VERSION 5.8 ;
BUSBITCHARS "[]" ;
DIVIDERCHAR "/" ;

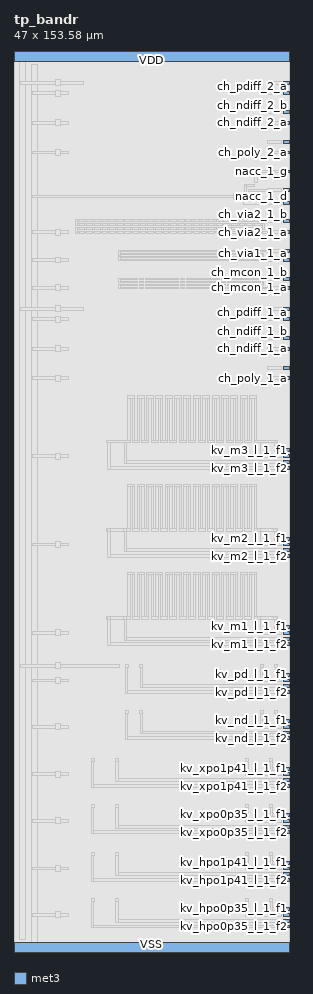
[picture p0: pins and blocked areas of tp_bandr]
MACRO tp_bandr
  CLASS BLOCK ;
  FOREIGN tp_bandr 0 0 ;
  ORIGIN 0 0 ;
  SIZE 47.000 BY 153.580 ;
  SYMMETRY X Y ;
  PIN VDD
    DIRECTION INOUT ;
    USE POWER ;
    PORT
      LAYER met3 ;
        RECT 0.000 151.980 47.000 153.580 ;
    END
  END VDD
  PIN VSS
    DIRECTION INOUT ;
    USE GROUND ;
    PORT
      LAYER met3 ;
        RECT 0.000 0.000 47.000 1.600 ;
    END
  END VSS
  PIN ch_mcon_1_a
    DIRECTION INOUT ;
    USE SIGNAL ;
    PORT
      LAYER met3 ;
        RECT 46.000 113.085 47.000 113.585 ;
    END
  END ch_mcon_1_a
  PIN ch_mcon_1_b
    DIRECTION INOUT ;
    USE SIGNAL ;
    PORT
      LAYER met3 ;
        RECT 46.000 114.585 47.000 115.085 ;
    END
  END ch_mcon_1_b
  PIN ch_ndiff_1_a
    DIRECTION INOUT ;
    USE SIGNAL ;
    PORT
      LAYER met3 ;
        RECT 46.000 102.685 47.000 103.185 ;
    END
  END ch_ndiff_1_a
  PIN ch_ndiff_1_b
    DIRECTION INOUT ;
    USE SIGNAL ;
    PORT
      LAYER met3 ;
        RECT 46.000 104.485 47.000 104.985 ;
    END
  END ch_ndiff_1_b
  PIN ch_ndiff_2_a
    DIRECTION INOUT ;
    USE SIGNAL ;
    PORT
      LAYER met3 ;
        RECT 46.000 141.235 47.000 141.735 ;
    END
  END ch_ndiff_2_a
  PIN ch_ndiff_2_b
    DIRECTION INOUT ;
    USE SIGNAL ;
    PORT
      LAYER met3 ;
        RECT 46.000 143.035 47.000 143.535 ;
    END
  END ch_ndiff_2_b
  PIN ch_pdiff_1_a
    DIRECTION INOUT ;
    USE SIGNAL ;
    PORT
      LAYER met3 ;
        RECT 46.000 107.735 47.000 108.235 ;
    END
  END ch_pdiff_1_a
  PIN ch_pdiff_1_b
    DIRECTION INOUT ;
    USE SIGNAL ;
    PORT
      LAYER met3 ;
        RECT 46.000 109.535 47.000 110.035 ;
    END
  END ch_pdiff_1_b
  PIN ch_pdiff_2_a
    DIRECTION INOUT ;
    USE SIGNAL ;
    PORT
      LAYER met3 ;
        RECT 46.000 146.285 47.000 146.785 ;
    END
  END ch_pdiff_2_a
  PIN ch_pdiff_2_b
    DIRECTION INOUT ;
    USE SIGNAL ;
    PORT
      LAYER met3 ;
        RECT 46.000 148.085 47.000 148.585 ;
    END
  END ch_pdiff_2_b
  PIN ch_poly_1_a
    DIRECTION INOUT ;
    USE SIGNAL ;
    PORT
      LAYER met3 ;
        RECT 46.000 97.635 47.000 98.135 ;
    END
  END ch_poly_1_a
  PIN ch_poly_1_b
    DIRECTION INOUT ;
    USE SIGNAL ;
    PORT
      LAYER met3 ;
        RECT 46.000 99.435 47.000 99.935 ;
    END
  END ch_poly_1_b
  PIN ch_poly_2_a
    DIRECTION INOUT ;
    USE SIGNAL ;
    PORT
      LAYER met3 ;
        RECT 46.000 136.185 47.000 136.685 ;
    END
  END ch_poly_2_a
  PIN ch_poly_2_b
    DIRECTION INOUT ;
    USE SIGNAL ;
    PORT
      LAYER met3 ;
        RECT 46.000 137.985 47.000 138.485 ;
    END
  END ch_poly_2_b
  PIN ch_via1_1_a
    DIRECTION INOUT ;
    USE SIGNAL ;
    PORT
      LAYER met3 ;
        RECT 46.000 117.835 47.000 118.335 ;
    END
  END ch_via1_1_a
  PIN ch_via1_1_b
    DIRECTION INOUT ;
    USE SIGNAL ;
    PORT
      LAYER met3 ;
        RECT 46.000 119.335 47.000 119.835 ;
    END
  END ch_via1_1_b
  PIN ch_via2_1_a
    DIRECTION INOUT ;
    USE SIGNAL ;
    PORT
      LAYER met3 ;
        RECT 46.000 122.585 47.000 123.085 ;
    END
  END ch_via2_1_a
  PIN ch_via2_1_b
    DIRECTION INOUT ;
    USE SIGNAL ;
    PORT
      LAYER met3 ;
        RECT 46.000 124.535 47.000 125.035 ;
    END
  END ch_via2_1_b
  PIN kv_hpo0p35_l_1_f1
    DIRECTION INOUT ;
    USE SIGNAL ;
    PORT
      LAYER met3 ;
        RECT 46.000 7.100 47.000 7.600 ;
    END
  END kv_hpo0p35_l_1_f1
  PIN kv_hpo0p35_l_1_f2
    DIRECTION INOUT ;
    USE SIGNAL ;
    PORT
      LAYER met3 ;
        RECT 46.000 4.100 47.000 4.600 ;
    END
  END kv_hpo0p35_l_1_f2
  PIN kv_hpo0p35_l_1_s1
    DIRECTION INOUT ;
    USE SIGNAL ;
    PORT
      LAYER met3 ;
        RECT 46.000 6.100 47.000 6.600 ;
    END
  END kv_hpo0p35_l_1_s1
  PIN kv_hpo0p35_l_1_s2
    DIRECTION INOUT ;
    USE SIGNAL ;
    PORT
      LAYER met3 ;
        RECT 46.000 5.100 47.000 5.600 ;
    END
  END kv_hpo0p35_l_1_s2
  PIN kv_hpo1p41_l_1_f1
    DIRECTION INOUT ;
    USE SIGNAL ;
    PORT
      LAYER met3 ;
        RECT 46.000 15.000 47.000 15.500 ;
    END
  END kv_hpo1p41_l_1_f1
  PIN kv_hpo1p41_l_1_f2
    DIRECTION INOUT ;
    USE SIGNAL ;
    PORT
      LAYER met3 ;
        RECT 46.000 12.000 47.000 12.500 ;
    END
  END kv_hpo1p41_l_1_f2
  PIN kv_hpo1p41_l_1_s1
    DIRECTION INOUT ;
    USE SIGNAL ;
    PORT
      LAYER met3 ;
        RECT 46.000 14.000 47.000 14.500 ;
    END
  END kv_hpo1p41_l_1_s1
  PIN kv_hpo1p41_l_1_s2
    DIRECTION INOUT ;
    USE SIGNAL ;
    PORT
      LAYER met3 ;
        RECT 46.000 13.000 47.000 13.500 ;
    END
  END kv_hpo1p41_l_1_s2
  PIN kv_m1_l_1_f1
    DIRECTION INOUT ;
    USE SIGNAL ;
    PORT
      LAYER met3 ;
        RECT 46.000 55.235 47.000 55.735 ;
    END
  END kv_m1_l_1_f1
  PIN kv_m1_l_1_f2
    DIRECTION INOUT ;
    USE SIGNAL ;
    PORT
      LAYER met3 ;
        RECT 46.000 52.235 47.000 52.735 ;
    END
  END kv_m1_l_1_f2
  PIN kv_m1_l_1_s1
    DIRECTION INOUT ;
    USE SIGNAL ;
    PORT
      LAYER met3 ;
        RECT 46.000 54.235 47.000 54.735 ;
    END
  END kv_m1_l_1_s1
  PIN kv_m1_l_1_s2
    DIRECTION INOUT ;
    USE SIGNAL ;
    PORT
      LAYER met3 ;
        RECT 46.000 53.235 47.000 53.735 ;
    END
  END kv_m1_l_1_s2
  PIN kv_m2_l_1_f1
    DIRECTION INOUT ;
    USE SIGNAL ;
    PORT
      LAYER met3 ;
        RECT 46.000 70.285 47.000 70.785 ;
    END
  END kv_m2_l_1_f1
  PIN kv_m2_l_1_f2
    DIRECTION INOUT ;
    USE SIGNAL ;
    PORT
      LAYER met3 ;
        RECT 46.000 67.285 47.000 67.785 ;
    END
  END kv_m2_l_1_f2
  PIN kv_m2_l_1_s1
    DIRECTION INOUT ;
    USE SIGNAL ;
    PORT
      LAYER met3 ;
        RECT 46.000 69.285 47.000 69.785 ;
    END
  END kv_m2_l_1_s1
  PIN kv_m2_l_1_s2
    DIRECTION INOUT ;
    USE SIGNAL ;
    PORT
      LAYER met3 ;
        RECT 46.000 68.285 47.000 68.785 ;
    END
  END kv_m2_l_1_s2
  PIN kv_m3_l_1_f1
    DIRECTION INOUT ;
    USE SIGNAL ;
    PORT
      LAYER met3 ;
        RECT 46.000 85.335 47.000 85.835 ;
    END
  END kv_m3_l_1_f1
  PIN kv_m3_l_1_f2
    DIRECTION INOUT ;
    USE SIGNAL ;
    PORT
      LAYER met3 ;
        RECT 46.000 82.335 47.000 82.835 ;
    END
  END kv_m3_l_1_f2
  PIN kv_m3_l_1_s1
    DIRECTION INOUT ;
    USE SIGNAL ;
    PORT
      LAYER met3 ;
        RECT 46.000 84.335 47.000 84.835 ;
    END
  END kv_m3_l_1_s1
  PIN kv_m3_l_1_s2
    DIRECTION INOUT ;
    USE SIGNAL ;
    PORT
      LAYER met3 ;
        RECT 46.000 83.335 47.000 83.835 ;
    END
  END kv_m3_l_1_s2
  PIN kv_nd_l_1_f1
    DIRECTION INOUT ;
    USE SIGNAL ;
    PORT
      LAYER met3 ;
        RECT 46.000 39.210 47.000 39.710 ;
    END
  END kv_nd_l_1_f1
  PIN kv_nd_l_1_f2
    DIRECTION INOUT ;
    USE SIGNAL ;
    PORT
      LAYER met3 ;
        RECT 46.000 36.210 47.000 36.710 ;
    END
  END kv_nd_l_1_f2
  PIN kv_nd_l_1_s1
    DIRECTION INOUT ;
    USE SIGNAL ;
    PORT
      LAYER met3 ;
        RECT 46.000 38.210 47.000 38.710 ;
    END
  END kv_nd_l_1_s1
  PIN kv_nd_l_1_s2
    DIRECTION INOUT ;
    USE SIGNAL ;
    PORT
      LAYER met3 ;
        RECT 46.000 37.210 47.000 37.710 ;
    END
  END kv_nd_l_1_s2
  PIN kv_pd_l_1_f1
    DIRECTION INOUT ;
    USE SIGNAL ;
    PORT
      LAYER met3 ;
        RECT 46.000 47.085 47.000 47.585 ;
    END
  END kv_pd_l_1_f1
  PIN kv_pd_l_1_f2
    DIRECTION INOUT ;
    USE SIGNAL ;
    PORT
      LAYER met3 ;
        RECT 46.000 44.085 47.000 44.585 ;
    END
  END kv_pd_l_1_f2
  PIN kv_pd_l_1_s1
    DIRECTION INOUT ;
    USE SIGNAL ;
    PORT
      LAYER met3 ;
        RECT 46.000 46.085 47.000 46.585 ;
    END
  END kv_pd_l_1_s1
  PIN kv_pd_l_1_s2
    DIRECTION INOUT ;
    USE SIGNAL ;
    PORT
      LAYER met3 ;
        RECT 46.000 45.085 47.000 45.585 ;
    END
  END kv_pd_l_1_s2
  PIN kv_xpo0p35_l_1_f1
    DIRECTION INOUT ;
    USE SIGNAL ;
    PORT
      LAYER met3 ;
        RECT 46.000 23.155 47.000 23.655 ;
    END
  END kv_xpo0p35_l_1_f1
  PIN kv_xpo0p35_l_1_f2
    DIRECTION INOUT ;
    USE SIGNAL ;
    PORT
      LAYER met3 ;
        RECT 46.000 20.155 47.000 20.655 ;
    END
  END kv_xpo0p35_l_1_f2
  PIN kv_xpo0p35_l_1_s1
    DIRECTION INOUT ;
    USE SIGNAL ;
    PORT
      LAYER met3 ;
        RECT 46.000 22.155 47.000 22.655 ;
    END
  END kv_xpo0p35_l_1_s1
  PIN kv_xpo0p35_l_1_s2
    DIRECTION INOUT ;
    USE SIGNAL ;
    PORT
      LAYER met3 ;
        RECT 46.000 21.155 47.000 21.655 ;
    END
  END kv_xpo0p35_l_1_s2
  PIN kv_xpo1p41_l_1_f1
    DIRECTION INOUT ;
    USE SIGNAL ;
    PORT
      LAYER met3 ;
        RECT 46.000 31.055 47.000 31.555 ;
    END
  END kv_xpo1p41_l_1_f1
  PIN kv_xpo1p41_l_1_f2
    DIRECTION INOUT ;
    USE SIGNAL ;
    PORT
      LAYER met3 ;
        RECT 46.000 28.055 47.000 28.555 ;
    END
  END kv_xpo1p41_l_1_f2
  PIN kv_xpo1p41_l_1_s1
    DIRECTION INOUT ;
    USE SIGNAL ;
    PORT
      LAYER met3 ;
        RECT 46.000 30.055 47.000 30.555 ;
    END
  END kv_xpo1p41_l_1_s1
  PIN kv_xpo1p41_l_1_s2
    DIRECTION INOUT ;
    USE SIGNAL ;
    PORT
      LAYER met3 ;
        RECT 46.000 29.055 47.000 29.555 ;
    END
  END kv_xpo1p41_l_1_s2
  PIN nacc_1_d
    DIRECTION INOUT ;
    USE SIGNAL ;
    PORT
      LAYER met3 ;
        RECT 46.000 127.535 47.000 128.035 ;
    END
  END nacc_1_d
  PIN nacc_1_g
    DIRECTION INOUT ;
    USE SIGNAL ;
    PORT
      LAYER met3 ;
        RECT 46.000 132.935 47.000 133.435 ;
    END
  END nacc_1_g
  PIN nacc_1_s
    DIRECTION INOUT ;
    USE SIGNAL ;
    PORT
      LAYER met3 ;
        RECT 46.000 129.725 47.000 130.225 ;
    END
  END nacc_1_s
  OBS
    LAYER li1 ;
      RECT 0.000 0.000 47.000 153.580 ;
    LAYER met1 ;
      RECT 19.400 57.185 19.800 64.385 ;
      RECT 15.800 56.785 19.800 57.185 ;
      RECT 21.000 57.185 21.400 64.385 ;
      RECT 20.200 56.785 21.400 57.185 ;
      RECT 22.600 57.185 23.000 64.385 ;
      RECT 21.800 56.785 23.000 57.185 ;
      RECT 24.200 57.185 24.600 64.385 ;
      RECT 23.400 56.785 24.600 57.185 ;
      RECT 25.800 57.185 26.200 64.385 ;
      RECT 25.000 56.785 26.200 57.185 ;
      RECT 27.400 57.185 27.800 64.385 ;
      RECT 26.600 56.785 27.800 57.185 ;
      RECT 29.000 57.185 29.400 64.385 ;
      RECT 28.200 56.785 29.400 57.185 ;
      RECT 30.600 57.185 31.000 64.385 ;
      RECT 29.800 56.785 31.000 57.185 ;
      RECT 32.200 57.185 32.600 64.385 ;
      RECT 31.400 56.785 32.600 57.185 ;
      RECT 33.800 57.185 34.200 64.385 ;
      RECT 33.000 56.785 34.200 57.185 ;
      RECT 35.400 57.185 35.800 64.385 ;
      RECT 34.600 56.785 35.800 57.185 ;
      RECT 37.000 57.185 37.400 64.385 ;
      RECT 36.200 56.785 37.400 57.185 ;
      RECT 38.600 57.185 39.000 64.385 ;
      RECT 37.800 56.785 39.000 57.185 ;
      RECT 40.200 57.185 40.600 64.385 ;
      RECT 39.400 56.785 40.600 57.185 ;
      RECT 19.400 64.385 20.600 64.785 ;
      RECT 20.200 57.185 20.600 64.385 ;
      RECT 21.000 64.385 22.200 64.785 ;
      RECT 21.800 57.185 22.200 64.385 ;
      RECT 22.600 64.385 23.800 64.785 ;
      RECT 23.400 57.185 23.800 64.385 ;
      RECT 24.200 64.385 25.400 64.785 ;
      RECT 25.000 57.185 25.400 64.385 ;
      RECT 25.800 64.385 27.000 64.785 ;
      RECT 26.600 57.185 27.000 64.385 ;
      RECT 27.400 64.385 28.600 64.785 ;
      RECT 28.200 57.185 28.600 64.385 ;
      RECT 29.000 64.385 30.200 64.785 ;
      RECT 29.800 57.185 30.200 64.385 ;
      RECT 30.600 64.385 31.800 64.785 ;
      RECT 31.400 57.185 31.800 64.385 ;
      RECT 32.200 64.385 33.400 64.785 ;
      RECT 33.000 57.185 33.400 64.385 ;
      RECT 33.800 64.385 35.000 64.785 ;
      RECT 34.600 57.185 35.000 64.385 ;
      RECT 35.400 64.385 36.600 64.785 ;
      RECT 36.200 57.185 36.600 64.385 ;
      RECT 37.000 64.385 38.200 64.785 ;
      RECT 37.800 57.185 38.200 64.385 ;
      RECT 38.600 64.385 39.800 64.785 ;
      RECT 39.400 57.185 39.800 64.385 ;
      RECT 41.000 56.785 45.000 57.185 ;
      RECT 40.200 64.385 41.400 64.785 ;
      RECT 41.000 57.185 41.400 64.385 ;
      RECT 26.355 113.220 27.145 113.450 ;
      RECT 26.355 113.720 27.145 113.950 ;
      RECT 26.355 114.220 27.145 114.450 ;
      RECT 26.355 114.720 27.145 114.950 ;
      RECT 26.840 117.955 27.660 118.215 ;
      RECT 26.840 118.455 27.660 118.715 ;
      RECT 26.840 118.955 27.660 119.215 ;
      RECT 26.840 119.455 27.660 119.715 ;
      RECT 35.355 113.220 36.145 113.450 ;
      RECT 35.355 113.720 36.145 113.950 ;
      RECT 35.355 114.220 36.145 114.450 ;
      RECT 35.355 114.720 36.145 114.950 ;
      RECT 35.840 117.955 36.660 118.215 ;
      RECT 35.840 118.455 36.660 118.715 ;
      RECT 35.840 118.955 36.660 119.215 ;
      RECT 35.840 119.455 36.660 119.715 ;
      RECT 36.355 113.220 37.145 113.450 ;
      RECT 36.355 113.720 37.145 113.950 ;
      RECT 37.355 113.720 38.145 113.950 ;
      RECT 38.355 113.720 39.145 113.950 ;
      RECT 39.355 113.720 40.145 113.950 ;
      RECT 40.355 113.720 41.145 113.950 ;
      RECT 41.355 113.720 42.145 113.950 ;
      RECT 37.355 113.220 38.145 113.450 ;
      RECT 36.355 114.220 37.145 114.450 ;
      RECT 37.355 114.220 38.145 114.450 ;
      RECT 38.355 114.220 39.145 114.450 ;
      RECT 39.355 114.220 40.145 114.450 ;
      RECT 40.355 114.220 41.145 114.450 ;
      RECT 41.355 114.220 42.145 114.450 ;
      RECT 42.385 113.690 42.615 114.480 ;
      RECT 38.355 113.220 39.145 113.450 ;
      RECT 36.355 114.720 37.145 114.950 ;
      RECT 37.355 114.720 38.145 114.950 ;
      RECT 38.355 114.720 39.145 114.950 ;
      RECT 39.355 114.720 40.145 114.950 ;
      RECT 40.355 114.720 41.145 114.950 ;
      RECT 41.355 114.720 42.145 114.950 ;
      RECT 42.355 114.720 43.340 114.950 ;
      RECT 43.340 114.675 43.660 114.995 ;
      RECT 39.355 113.220 40.145 113.450 ;
      RECT 36.840 117.955 37.660 118.215 ;
      RECT 37.840 117.955 38.660 118.215 ;
      RECT 38.840 117.955 39.660 118.215 ;
      RECT 39.840 117.955 40.660 118.215 ;
      RECT 40.840 117.955 41.660 118.215 ;
      RECT 41.840 117.955 42.660 118.215 ;
      RECT 40.355 113.220 41.145 113.450 ;
      RECT 36.840 118.455 37.660 118.715 ;
      RECT 37.840 118.455 38.660 118.715 ;
      RECT 38.840 118.455 39.660 118.715 ;
      RECT 39.840 118.455 40.660 118.715 ;
      RECT 40.840 118.455 41.660 118.715 ;
      RECT 41.840 118.455 42.660 118.715 ;
      RECT 41.355 113.220 42.145 113.450 ;
      RECT 36.840 118.955 37.660 119.215 ;
      RECT 37.840 118.955 38.660 119.215 ;
      RECT 38.840 118.955 39.660 119.215 ;
      RECT 39.840 118.955 40.660 119.215 ;
      RECT 40.840 118.955 41.660 119.215 ;
      RECT 41.840 118.955 42.660 119.215 ;
      RECT 42.355 113.220 43.340 113.450 ;
      RECT 43.340 113.175 43.660 113.495 ;
      RECT 36.840 119.455 37.660 119.715 ;
      RECT 37.840 119.455 38.660 119.715 ;
      RECT 38.840 119.455 39.660 119.715 ;
      RECT 39.840 119.455 40.660 119.715 ;
      RECT 40.840 119.455 41.660 119.715 ;
      RECT 41.840 119.455 42.660 119.715 ;
      RECT 40.000 128.545 41.820 129.295 ;
      RECT 39.980 129.830 43.390 130.120 ;
      RECT 43.710 129.830 43.800 130.120 ;
      RECT 43.390 129.815 43.710 130.135 ;
      RECT 39.335 130.630 41.055 130.920 ;
      RECT 41.150 131.345 41.470 131.665 ;
      RECT 43.340 136.275 43.660 136.595 ;
      RECT 43.340 138.075 43.660 138.395 ;
      RECT 43.340 141.325 43.660 141.645 ;
      RECT 43.340 143.125 43.660 143.445 ;
      RECT 43.340 146.375 43.660 146.695 ;
      RECT 43.340 148.175 43.660 148.495 ;
      RECT 34.840 117.955 35.660 118.215 ;
      RECT 28.355 114.220 29.145 114.450 ;
      RECT 29.355 114.220 30.145 114.450 ;
      RECT 30.355 114.220 31.145 114.450 ;
      RECT 31.355 114.220 32.145 114.450 ;
      RECT 32.355 114.220 33.145 114.450 ;
      RECT 33.355 114.220 34.145 114.450 ;
      RECT 34.355 114.220 35.145 114.450 ;
      RECT 27.840 118.455 28.660 118.715 ;
      RECT 28.840 118.455 29.660 118.715 ;
      RECT 29.840 118.455 30.660 118.715 ;
      RECT 30.840 118.455 31.660 118.715 ;
      RECT 31.840 118.455 32.660 118.715 ;
      RECT 32.840 118.455 33.660 118.715 ;
      RECT 33.840 118.455 34.660 118.715 ;
      RECT 34.840 118.455 35.660 118.715 ;
      RECT 27.355 113.720 28.145 113.950 ;
      RECT 28.355 113.720 29.145 113.950 ;
      RECT 29.355 113.720 30.145 113.950 ;
      RECT 30.355 113.720 31.145 113.950 ;
      RECT 31.355 113.720 32.145 113.950 ;
      RECT 32.355 113.720 33.145 113.950 ;
      RECT 33.355 113.720 34.145 113.950 ;
      RECT 27.840 118.955 28.660 119.215 ;
      RECT 28.840 118.955 29.660 119.215 ;
      RECT 29.840 118.955 30.660 119.215 ;
      RECT 30.840 118.955 31.660 119.215 ;
      RECT 31.840 118.955 32.660 119.215 ;
      RECT 32.840 118.955 33.660 119.215 ;
      RECT 33.840 118.955 34.660 119.215 ;
      RECT 34.840 118.955 35.660 119.215 ;
      RECT 34.355 113.720 35.145 113.950 ;
      RECT 27.355 114.720 28.145 114.950 ;
      RECT 28.355 114.720 29.145 114.950 ;
      RECT 29.355 114.720 30.145 114.950 ;
      RECT 30.355 114.720 31.145 114.950 ;
      RECT 31.355 114.720 32.145 114.950 ;
      RECT 32.355 114.720 33.145 114.950 ;
      RECT 27.355 113.220 28.145 113.450 ;
      RECT 27.840 119.455 28.660 119.715 ;
      RECT 28.840 119.455 29.660 119.715 ;
      RECT 29.840 119.455 30.660 119.715 ;
      RECT 30.840 119.455 31.660 119.715 ;
      RECT 31.840 119.455 32.660 119.715 ;
      RECT 32.840 119.455 33.660 119.715 ;
      RECT 33.840 119.455 34.660 119.715 ;
      RECT 34.840 119.455 35.660 119.715 ;
      RECT 33.355 114.720 34.145 114.950 ;
      RECT 34.355 114.720 35.145 114.950 ;
      RECT 29.355 113.220 30.145 113.450 ;
      RECT 30.355 113.220 31.145 113.450 ;
      RECT 31.355 113.220 32.145 113.450 ;
      RECT 32.355 113.220 33.145 113.450 ;
      RECT 33.355 113.220 34.145 113.450 ;
      RECT 34.355 113.220 35.145 113.450 ;
      RECT 28.355 113.220 29.145 113.450 ;
      RECT 27.355 114.220 28.145 114.450 ;
      RECT 27.840 117.955 28.660 118.215 ;
      RECT 28.840 117.955 29.660 118.215 ;
      RECT 29.840 117.955 30.660 118.215 ;
      RECT 30.840 117.955 31.660 118.215 ;
      RECT 31.840 117.955 32.660 118.215 ;
      RECT 32.840 117.955 33.660 118.215 ;
      RECT 33.840 117.955 34.660 118.215 ;
      RECT 43.340 97.725 43.660 98.045 ;
      RECT 43.340 107.825 43.660 108.145 ;
      RECT 43.340 102.775 43.660 103.095 ;
      RECT 43.340 104.575 43.660 104.895 ;
      RECT 43.340 99.525 43.660 99.845 ;
      RECT 43.340 109.625 43.660 109.945 ;
      RECT 25.840 118.455 26.660 118.715 ;
      RECT 20.355 114.720 21.145 114.950 ;
      RECT 21.355 114.720 22.145 114.950 ;
      RECT 22.355 114.720 23.145 114.950 ;
      RECT 23.355 114.720 24.145 114.950 ;
      RECT 24.355 114.720 25.145 114.950 ;
      RECT 25.355 114.720 26.145 114.950 ;
      RECT 8.840 102.775 9.160 103.095 ;
      RECT 8.840 113.175 9.160 113.495 ;
      RECT 11.440 109.625 11.760 109.945 ;
      RECT 18.355 113.720 19.145 113.950 ;
      RECT 19.355 113.720 20.145 113.950 ;
      RECT 17.885 113.190 18.115 113.980 ;
      RECT 18.355 114.220 19.145 114.450 ;
      RECT 19.355 114.220 20.145 114.450 ;
      RECT 20.355 114.220 21.145 114.450 ;
      RECT 21.355 114.220 22.145 114.450 ;
      RECT 17.840 118.955 18.660 119.215 ;
      RECT 18.840 118.955 19.660 119.215 ;
      RECT 19.840 118.955 20.660 119.215 ;
      RECT 20.840 118.955 21.660 119.215 ;
      RECT 21.840 118.955 22.660 119.215 ;
      RECT 22.840 118.955 23.660 119.215 ;
      RECT 23.840 118.955 24.660 119.215 ;
      RECT 24.840 118.955 25.660 119.215 ;
      RECT 25.840 118.955 26.660 119.215 ;
      RECT 22.355 114.220 23.145 114.450 ;
      RECT 23.355 114.220 24.145 114.450 ;
      RECT 24.355 114.220 25.145 114.450 ;
      RECT 25.355 114.220 26.145 114.450 ;
      RECT 20.355 113.720 21.145 113.950 ;
      RECT 21.355 113.720 22.145 113.950 ;
      RECT 17.885 114.190 18.115 114.980 ;
      RECT 22.355 113.720 23.145 113.950 ;
      RECT 17.840 117.955 18.660 118.215 ;
      RECT 18.840 117.955 19.660 118.215 ;
      RECT 19.840 117.955 20.660 118.215 ;
      RECT 20.840 117.955 21.660 118.215 ;
      RECT 21.840 117.955 22.660 118.215 ;
      RECT 22.840 117.955 23.660 118.215 ;
      RECT 23.840 117.955 24.660 118.215 ;
      RECT 24.840 117.955 25.660 118.215 ;
      RECT 17.840 119.455 18.660 119.715 ;
      RECT 18.840 119.455 19.660 119.715 ;
      RECT 19.840 119.455 20.660 119.715 ;
      RECT 20.840 119.455 21.660 119.715 ;
      RECT 21.840 119.455 22.660 119.715 ;
      RECT 22.840 119.455 23.660 119.715 ;
      RECT 23.840 119.455 24.660 119.715 ;
      RECT 24.840 119.455 25.660 119.715 ;
      RECT 25.840 119.455 26.660 119.715 ;
      RECT 25.840 117.955 26.660 118.215 ;
      RECT 23.355 113.720 24.145 113.950 ;
      RECT 24.355 113.720 25.145 113.950 ;
      RECT 25.355 113.720 26.145 113.950 ;
      RECT 8.840 84.425 9.160 84.745 ;
      RECT 18.355 113.220 19.145 113.450 ;
      RECT 19.355 113.220 20.145 113.450 ;
      RECT 20.355 113.220 21.145 113.450 ;
      RECT 21.355 113.220 22.145 113.450 ;
      RECT 22.355 113.220 23.145 113.450 ;
      RECT 23.355 113.220 24.145 113.450 ;
      RECT 24.355 113.220 25.145 113.450 ;
      RECT 25.355 113.220 26.145 113.450 ;
      RECT 8.840 97.725 9.160 98.045 ;
      RECT 8.840 107.825 9.160 108.145 ;
      RECT 18.355 114.720 19.145 114.950 ;
      RECT 8.840 122.675 9.160 122.995 ;
      RECT 19.355 114.720 20.145 114.950 ;
      RECT 8.840 117.925 9.160 118.245 ;
      RECT 17.840 118.455 18.660 118.715 ;
      RECT 18.840 118.455 19.660 118.715 ;
      RECT 8.840 136.275 9.160 136.595 ;
      RECT 19.840 118.455 20.660 118.715 ;
      RECT 20.840 118.455 21.660 118.715 ;
      RECT 8.840 141.325 9.160 141.645 ;
      RECT 21.840 118.455 22.660 118.715 ;
      RECT 22.840 118.455 23.660 118.715 ;
      RECT 8.840 146.375 9.160 146.695 ;
      RECT 23.840 118.455 24.660 118.715 ;
      RECT 11.440 148.175 11.760 148.495 ;
      RECT 24.840 118.455 25.660 118.715 ;
      RECT 8.840 6.190 9.160 6.510 ;
      RECT 8.840 69.375 9.160 69.695 ;
      RECT 13.280 8.690 13.600 9.010 ;
      RECT 17.440 8.690 17.760 9.010 ;
      RECT 8.840 14.090 9.160 14.410 ;
      RECT 13.280 16.590 13.600 16.910 ;
      RECT 17.440 16.590 17.760 16.910 ;
      RECT 8.840 22.245 9.160 22.565 ;
      RECT 13.280 24.745 13.600 25.065 ;
      RECT 17.440 24.745 17.760 25.065 ;
      RECT 8.840 30.145 9.160 30.465 ;
      RECT 13.280 32.645 13.600 32.965 ;
      RECT 17.440 32.645 17.760 32.965 ;
      RECT 8.840 38.300 9.160 38.620 ;
      RECT 19.090 40.800 19.410 41.120 ;
      RECT 21.590 40.800 21.910 41.120 ;
      RECT 8.840 46.175 9.160 46.495 ;
      RECT 17.540 48.675 17.860 48.995 ;
      RECT 19.090 48.675 19.410 48.995 ;
      RECT 21.590 48.675 21.910 48.995 ;
      RECT 8.840 54.325 9.160 54.645 ;
      RECT 42.090 40.800 42.410 41.120 ;
      RECT 44.590 40.800 44.910 41.120 ;
      RECT 43.760 16.590 44.080 16.910 ;
      RECT 43.760 8.690 44.080 9.010 ;
      RECT 39.600 8.690 39.920 9.010 ;
      RECT 39.600 32.645 39.920 32.965 ;
      RECT 42.090 48.675 42.410 48.995 ;
      RECT 44.590 48.675 44.910 48.995 ;
      RECT 43.760 32.645 44.080 32.965 ;
      RECT 39.600 16.590 39.920 16.910 ;
      RECT 39.600 24.745 39.920 25.065 ;
      RECT 43.760 24.745 44.080 25.065 ;
    LAYER met2 ;
      RECT 19.400 72.235 19.800 79.435 ;
      RECT 15.800 71.835 19.800 72.235 ;
      RECT 21.000 72.235 21.400 79.435 ;
      RECT 20.200 71.835 21.400 72.235 ;
      RECT 22.600 72.235 23.000 79.435 ;
      RECT 21.800 71.835 23.000 72.235 ;
      RECT 24.200 72.235 24.600 79.435 ;
      RECT 23.400 71.835 24.600 72.235 ;
      RECT 25.800 72.235 26.200 79.435 ;
      RECT 25.000 71.835 26.200 72.235 ;
      RECT 27.400 72.235 27.800 79.435 ;
      RECT 26.600 71.835 27.800 72.235 ;
      RECT 29.000 72.235 29.400 79.435 ;
      RECT 28.200 71.835 29.400 72.235 ;
      RECT 30.600 72.235 31.000 79.435 ;
      RECT 29.800 71.835 31.000 72.235 ;
      RECT 32.200 72.235 32.600 79.435 ;
      RECT 31.400 71.835 32.600 72.235 ;
      RECT 33.800 72.235 34.200 79.435 ;
      RECT 33.000 71.835 34.200 72.235 ;
      RECT 35.400 72.235 35.800 79.435 ;
      RECT 34.600 71.835 35.800 72.235 ;
      RECT 37.000 72.235 37.400 79.435 ;
      RECT 36.200 71.835 37.400 72.235 ;
      RECT 38.600 72.235 39.000 79.435 ;
      RECT 37.800 71.835 39.000 72.235 ;
      RECT 40.200 72.235 40.600 79.435 ;
      RECT 39.400 71.835 40.600 72.235 ;
      RECT 19.400 79.435 20.600 79.835 ;
      RECT 20.200 72.235 20.600 79.435 ;
      RECT 21.000 79.435 22.200 79.835 ;
      RECT 21.800 72.235 22.200 79.435 ;
      RECT 22.600 79.435 23.800 79.835 ;
      RECT 23.400 72.235 23.800 79.435 ;
      RECT 24.200 79.435 25.400 79.835 ;
      RECT 25.000 72.235 25.400 79.435 ;
      RECT 25.800 79.435 27.000 79.835 ;
      RECT 26.600 72.235 27.000 79.435 ;
      RECT 27.400 79.435 28.600 79.835 ;
      RECT 28.200 72.235 28.600 79.435 ;
      RECT 29.000 79.435 30.200 79.835 ;
      RECT 29.800 72.235 30.200 79.435 ;
      RECT 30.600 79.435 31.800 79.835 ;
      RECT 31.400 72.235 31.800 79.435 ;
      RECT 32.200 79.435 33.400 79.835 ;
      RECT 33.000 72.235 33.400 79.435 ;
      RECT 33.800 79.435 35.000 79.835 ;
      RECT 34.600 72.235 35.000 79.435 ;
      RECT 35.400 79.435 36.600 79.835 ;
      RECT 36.200 72.235 36.600 79.435 ;
      RECT 37.000 79.435 38.200 79.835 ;
      RECT 37.800 72.235 38.200 79.435 ;
      RECT 38.600 79.435 39.800 79.835 ;
      RECT 39.400 72.235 39.800 79.435 ;
      RECT 41.000 71.835 45.000 72.235 ;
      RECT 40.200 79.435 41.400 79.835 ;
      RECT 41.000 72.235 41.400 79.435 ;
      RECT 22.340 117.955 23.160 118.215 ;
      RECT 22.340 118.455 23.160 118.715 ;
      RECT 22.340 118.955 23.160 119.215 ;
      RECT 22.340 119.455 23.160 119.715 ;
      RECT 22.165 122.695 23.185 122.975 ;
      RECT 22.165 123.345 23.185 123.625 ;
      RECT 22.165 123.995 23.185 124.275 ;
      RECT 22.165 124.645 23.185 124.925 ;
      RECT 3.000 0.200 4.000 151.380 ;
      RECT 1.000 2.200 2.000 153.380 ;
      RECT 33.340 117.955 34.160 118.215 ;
      RECT 33.340 118.455 34.160 118.715 ;
      RECT 33.340 118.955 34.160 119.215 ;
      RECT 33.340 119.455 34.160 119.715 ;
      RECT 33.865 122.695 34.885 122.975 ;
      RECT 33.865 123.345 34.885 123.625 ;
      RECT 33.865 123.995 34.885 124.275 ;
      RECT 33.865 124.645 34.885 124.925 ;
      RECT 41.340 117.955 42.160 118.215 ;
      RECT 42.340 117.955 43.315 118.215 ;
      RECT 43.315 117.900 43.685 118.270 ;
      RECT 34.340 117.955 35.160 118.215 ;
      RECT 34.340 118.455 35.160 118.715 ;
      RECT 35.340 118.455 36.160 118.715 ;
      RECT 36.340 118.455 37.160 118.715 ;
      RECT 37.340 118.455 38.160 118.715 ;
      RECT 38.340 118.455 39.160 118.715 ;
      RECT 39.340 118.455 40.160 118.715 ;
      RECT 40.340 118.455 41.160 118.715 ;
      RECT 41.340 118.455 42.160 118.715 ;
      RECT 35.340 117.955 36.160 118.215 ;
      RECT 34.340 118.955 35.160 119.215 ;
      RECT 35.340 118.955 36.160 119.215 ;
      RECT 36.340 118.955 37.160 119.215 ;
      RECT 37.340 118.955 38.160 119.215 ;
      RECT 38.340 118.955 39.160 119.215 ;
      RECT 39.340 118.955 40.160 119.215 ;
      RECT 40.340 118.955 41.160 119.215 ;
      RECT 41.340 118.955 42.160 119.215 ;
      RECT 42.370 118.425 42.630 119.245 ;
      RECT 36.340 117.955 37.160 118.215 ;
      RECT 34.340 119.455 35.160 119.715 ;
      RECT 35.340 119.455 36.160 119.715 ;
      RECT 36.340 119.455 37.160 119.715 ;
      RECT 37.340 119.455 38.160 119.715 ;
      RECT 38.340 119.455 39.160 119.715 ;
      RECT 39.340 119.455 40.160 119.715 ;
      RECT 40.340 119.455 41.160 119.715 ;
      RECT 41.340 119.455 42.160 119.715 ;
      RECT 42.340 119.455 43.315 119.715 ;
      RECT 43.315 119.400 43.685 119.770 ;
      RECT 37.340 117.955 38.160 118.215 ;
      RECT 35.165 122.695 36.185 122.975 ;
      RECT 36.465 122.695 37.485 122.975 ;
      RECT 37.765 122.695 38.785 122.975 ;
      RECT 39.065 122.695 40.085 122.975 ;
      RECT 40.365 122.695 41.385 122.975 ;
      RECT 41.665 122.695 42.685 122.975 ;
      RECT 38.340 117.955 39.160 118.215 ;
      RECT 35.165 123.345 36.185 123.625 ;
      RECT 36.465 123.345 37.485 123.625 ;
      RECT 37.765 123.345 38.785 123.625 ;
      RECT 39.065 123.345 40.085 123.625 ;
      RECT 40.365 123.345 41.385 123.625 ;
      RECT 41.665 123.345 42.685 123.625 ;
      RECT 39.340 117.955 40.160 118.215 ;
      RECT 35.165 123.995 36.185 124.275 ;
      RECT 36.465 123.995 37.485 124.275 ;
      RECT 37.765 123.995 38.785 124.275 ;
      RECT 39.065 123.995 40.085 124.275 ;
      RECT 40.365 123.995 41.385 124.275 ;
      RECT 41.665 123.995 42.685 124.275 ;
      RECT 40.340 117.955 41.160 118.215 ;
      RECT 35.165 124.645 36.185 124.925 ;
      RECT 36.465 124.645 37.485 124.925 ;
      RECT 37.765 124.645 38.785 124.925 ;
      RECT 39.065 124.645 40.085 124.925 ;
      RECT 40.365 124.645 41.385 124.925 ;
      RECT 41.665 124.645 42.685 124.925 ;
      RECT 40.615 128.735 40.985 129.105 ;
      RECT 43.365 129.790 43.735 130.160 ;
      RECT 39.365 130.785 39.625 130.935 ;
      RECT 39.335 127.970 39.655 130.785 ;
      RECT 39.310 127.600 39.680 127.970 ;
      RECT 41.125 131.305 41.495 133.370 ;
      RECT 43.315 136.250 43.685 136.620 ;
      RECT 43.315 138.050 43.685 138.420 ;
      RECT 43.315 141.300 43.685 141.670 ;
      RECT 43.315 143.100 43.685 143.470 ;
      RECT 43.315 146.350 43.685 146.720 ;
      RECT 43.315 148.150 43.685 148.520 ;
      RECT 23.340 118.955 24.160 119.215 ;
      RECT 23.465 122.695 24.485 122.975 ;
      RECT 24.765 122.695 25.785 122.975 ;
      RECT 26.065 122.695 27.085 122.975 ;
      RECT 27.365 122.695 28.385 122.975 ;
      RECT 28.665 122.695 29.685 122.975 ;
      RECT 29.965 122.695 30.985 122.975 ;
      RECT 31.265 122.695 32.285 122.975 ;
      RECT 32.565 122.695 33.585 122.975 ;
      RECT 24.340 118.955 25.160 119.215 ;
      RECT 25.340 118.955 26.160 119.215 ;
      RECT 26.340 118.955 27.160 119.215 ;
      RECT 27.340 118.955 28.160 119.215 ;
      RECT 28.340 118.955 29.160 119.215 ;
      RECT 29.340 118.955 30.160 119.215 ;
      RECT 30.340 118.955 31.160 119.215 ;
      RECT 23.465 123.345 24.485 123.625 ;
      RECT 24.765 123.345 25.785 123.625 ;
      RECT 26.065 123.345 27.085 123.625 ;
      RECT 27.365 123.345 28.385 123.625 ;
      RECT 28.665 123.345 29.685 123.625 ;
      RECT 29.965 123.345 30.985 123.625 ;
      RECT 31.265 123.345 32.285 123.625 ;
      RECT 32.565 123.345 33.585 123.625 ;
      RECT 31.340 118.955 32.160 119.215 ;
      RECT 32.340 118.955 33.160 119.215 ;
      RECT 23.340 118.455 24.160 118.715 ;
      RECT 24.340 118.455 25.160 118.715 ;
      RECT 25.340 118.455 26.160 118.715 ;
      RECT 26.340 118.455 27.160 118.715 ;
      RECT 27.340 118.455 28.160 118.715 ;
      RECT 23.465 123.995 24.485 124.275 ;
      RECT 24.765 123.995 25.785 124.275 ;
      RECT 26.065 123.995 27.085 124.275 ;
      RECT 27.365 123.995 28.385 124.275 ;
      RECT 28.665 123.995 29.685 124.275 ;
      RECT 29.965 123.995 30.985 124.275 ;
      RECT 31.265 123.995 32.285 124.275 ;
      RECT 32.565 123.995 33.585 124.275 ;
      RECT 28.340 118.455 29.160 118.715 ;
      RECT 29.340 118.455 30.160 118.715 ;
      RECT 30.340 118.455 31.160 118.715 ;
      RECT 31.340 118.455 32.160 118.715 ;
      RECT 32.340 118.455 33.160 118.715 ;
      RECT 23.340 119.455 24.160 119.715 ;
      RECT 24.340 119.455 25.160 119.715 ;
      RECT 23.465 124.645 24.485 124.925 ;
      RECT 24.765 124.645 25.785 124.925 ;
      RECT 26.065 124.645 27.085 124.925 ;
      RECT 27.365 124.645 28.385 124.925 ;
      RECT 28.665 124.645 29.685 124.925 ;
      RECT 29.965 124.645 30.985 124.925 ;
      RECT 31.265 124.645 32.285 124.925 ;
      RECT 32.565 124.645 33.585 124.925 ;
      RECT 25.340 119.455 26.160 119.715 ;
      RECT 26.340 119.455 27.160 119.715 ;
      RECT 27.340 119.455 28.160 119.715 ;
      RECT 28.340 119.455 29.160 119.715 ;
      RECT 29.340 119.455 30.160 119.715 ;
      RECT 30.340 119.455 31.160 119.715 ;
      RECT 31.340 119.455 32.160 119.715 ;
      RECT 32.340 119.455 33.160 119.715 ;
      RECT 25.340 117.955 26.160 118.215 ;
      RECT 26.340 117.955 27.160 118.215 ;
      RECT 27.340 117.955 28.160 118.215 ;
      RECT 28.340 117.955 29.160 118.215 ;
      RECT 29.340 117.955 30.160 118.215 ;
      RECT 30.340 117.955 31.160 118.215 ;
      RECT 31.340 117.955 32.160 118.215 ;
      RECT 32.340 117.955 33.160 118.215 ;
      RECT 24.340 117.955 25.160 118.215 ;
      RECT 23.340 117.955 24.160 118.215 ;
      RECT 43.315 99.500 43.685 99.870 ;
      RECT 43.315 114.650 43.685 115.020 ;
      RECT 43.315 102.750 43.685 103.120 ;
      RECT 43.315 109.600 43.685 109.970 ;
      RECT 43.315 113.150 43.685 113.520 ;
      RECT 43.315 107.800 43.685 108.170 ;
      RECT 43.315 97.700 43.685 98.070 ;
      RECT 43.315 104.550 43.685 104.920 ;
      RECT 10.465 123.995 11.485 124.275 ;
      RECT 11.765 123.995 12.785 124.275 ;
      RECT 13.065 123.995 14.085 124.275 ;
      RECT 14.365 123.995 15.385 124.275 ;
      RECT 15.665 123.995 16.685 124.275 ;
      RECT 16.965 123.995 17.985 124.275 ;
      RECT 18.265 123.995 19.285 124.275 ;
      RECT 19.565 123.995 20.585 124.275 ;
      RECT 20.865 123.995 21.885 124.275 ;
      RECT 19.565 122.695 20.585 122.975 ;
      RECT 20.865 122.695 21.885 122.975 ;
      RECT 19.340 119.455 20.160 119.715 ;
      RECT 20.340 119.455 21.160 119.715 ;
      RECT 21.340 119.455 22.160 119.715 ;
      RECT 19.340 117.955 20.160 118.215 ;
      RECT 20.340 117.955 21.160 118.215 ;
      RECT 21.340 117.955 22.160 118.215 ;
      RECT 8.815 117.900 9.185 118.270 ;
      RECT 8.815 102.750 9.185 103.120 ;
      RECT 18.340 118.455 19.160 118.715 ;
      RECT 19.340 118.455 20.160 118.715 ;
      RECT 20.340 118.455 21.160 118.715 ;
      RECT 21.340 118.455 22.160 118.715 ;
      RECT 11.415 109.600 11.785 109.970 ;
      RECT 8.815 84.400 9.185 84.770 ;
      RECT 10.465 124.645 11.485 124.925 ;
      RECT 11.765 124.645 12.785 124.925 ;
      RECT 13.065 124.645 14.085 124.925 ;
      RECT 14.365 124.645 15.385 124.925 ;
      RECT 15.665 124.645 16.685 124.925 ;
      RECT 16.965 124.645 17.985 124.925 ;
      RECT 18.265 124.645 19.285 124.925 ;
      RECT 19.565 124.645 20.585 124.925 ;
      RECT 20.865 124.645 21.885 124.925 ;
      RECT 8.815 113.150 9.185 113.520 ;
      RECT 8.815 97.700 9.185 98.070 ;
      RECT 8.815 122.650 9.185 123.020 ;
      RECT 10.465 123.345 11.485 123.625 ;
      RECT 11.765 123.345 12.785 123.625 ;
      RECT 13.065 123.345 14.085 123.625 ;
      RECT 14.365 123.345 15.385 123.625 ;
      RECT 15.665 123.345 16.685 123.625 ;
      RECT 16.965 123.345 17.985 123.625 ;
      RECT 18.265 123.345 19.285 123.625 ;
      RECT 19.565 123.345 20.585 123.625 ;
      RECT 20.865 123.345 21.885 123.625 ;
      RECT 8.815 107.800 9.185 108.170 ;
      RECT 17.870 117.925 18.130 118.745 ;
      RECT 18.340 118.955 19.160 119.215 ;
      RECT 19.340 118.955 20.160 119.215 ;
      RECT 20.340 118.955 21.160 119.215 ;
      RECT 21.340 118.955 22.160 119.215 ;
      RECT 18.340 117.955 19.160 118.215 ;
      RECT 17.870 118.925 18.130 119.745 ;
      RECT 8.815 136.250 9.185 136.620 ;
      RECT 18.340 119.455 19.160 119.715 ;
      RECT 10.465 122.695 11.485 122.975 ;
      RECT 8.815 141.300 9.185 141.670 ;
      RECT 11.765 122.695 12.785 122.975 ;
      RECT 13.065 122.695 14.085 122.975 ;
      RECT 8.815 146.350 9.185 146.720 ;
      RECT 14.365 122.695 15.385 122.975 ;
      RECT 11.415 148.150 11.785 148.520 ;
      RECT 15.665 122.695 16.685 122.975 ;
      RECT 16.965 122.695 17.985 122.975 ;
      RECT 18.265 122.695 19.285 122.975 ;
      RECT 13.255 16.565 13.625 16.935 ;
      RECT 17.415 16.565 17.785 16.935 ;
      RECT 8.815 22.220 9.185 22.590 ;
      RECT 13.255 24.720 13.625 25.090 ;
      RECT 17.415 24.720 17.785 25.090 ;
      RECT 8.815 30.120 9.185 30.490 ;
      RECT 13.255 32.620 13.625 32.990 ;
      RECT 17.415 32.620 17.785 32.990 ;
      RECT 8.815 38.275 9.185 38.645 ;
      RECT 19.065 40.775 19.435 41.145 ;
      RECT 21.565 40.775 21.935 41.145 ;
      RECT 8.815 46.150 9.185 46.520 ;
      RECT 17.515 48.650 17.885 49.020 ;
      RECT 19.065 48.650 19.435 49.020 ;
      RECT 21.565 48.650 21.935 49.020 ;
      RECT 8.815 54.300 9.185 54.670 ;
      RECT 16.015 56.800 16.385 57.170 ;
      RECT 18.815 56.800 19.185 57.170 ;
      RECT 8.815 69.350 9.185 69.720 ;
      RECT 8.815 6.165 9.185 6.535 ;
      RECT 13.255 8.665 13.625 9.035 ;
      RECT 17.415 8.665 17.785 9.035 ;
      RECT 8.815 14.065 9.185 14.435 ;
      RECT 39.575 24.720 39.945 25.090 ;
      RECT 41.615 56.800 41.985 57.170 ;
      RECT 44.415 56.800 44.785 57.170 ;
      RECT 43.735 24.720 44.105 25.090 ;
      RECT 42.065 40.775 42.435 41.145 ;
      RECT 44.565 40.775 44.935 41.145 ;
      RECT 43.735 16.565 44.105 16.935 ;
      RECT 43.735 8.665 44.105 9.035 ;
      RECT 39.575 8.665 39.945 9.035 ;
      RECT 39.575 32.620 39.945 32.990 ;
      RECT 42.065 48.650 42.435 49.020 ;
      RECT 44.565 48.650 44.935 49.020 ;
      RECT 43.735 32.620 44.105 32.990 ;
      RECT 39.575 16.565 39.945 16.935 ;
    LAYER met3 ;
      RECT 13.190 8.600 13.690 9.100 ;
      RECT 13.640 4.100 45.700 4.600 ;
      RECT 13.240 4.100 13.640 8.600 ;
      RECT 17.350 8.600 17.850 9.100 ;
      RECT 17.800 5.100 45.700 5.600 ;
      RECT 17.400 5.100 17.800 8.600 ;
      RECT 13.190 16.500 13.690 17.000 ;
      RECT 13.640 12.000 45.700 12.500 ;
      RECT 13.240 12.000 13.640 16.500 ;
      RECT 17.350 16.500 17.850 17.000 ;
      RECT 17.800 13.000 45.700 13.500 ;
      RECT 17.400 13.000 17.800 16.500 ;
      RECT 13.190 24.655 13.690 25.155 ;
      RECT 13.640 20.155 45.700 20.655 ;
      RECT 13.240 20.155 13.640 24.655 ;
      RECT 17.350 24.655 17.850 25.155 ;
      RECT 17.800 21.155 45.700 21.655 ;
      RECT 17.400 21.155 17.800 24.655 ;
      RECT 13.190 32.555 13.690 33.055 ;
      RECT 13.640 28.055 45.700 28.555 ;
      RECT 13.240 28.055 13.640 32.555 ;
      RECT 17.350 32.555 17.850 33.055 ;
      RECT 17.800 29.055 45.700 29.555 ;
      RECT 17.400 29.055 17.800 32.555 ;
      RECT 19.000 40.710 19.500 41.210 ;
      RECT 19.450 36.210 45.700 36.710 ;
      RECT 19.050 36.210 19.450 40.710 ;
      RECT 21.500 40.710 22.000 41.210 ;
      RECT 21.950 37.210 45.700 37.710 ;
      RECT 21.550 37.210 21.950 40.710 ;
      RECT 19.000 48.585 19.500 49.085 ;
      RECT 19.450 44.085 45.700 44.585 ;
      RECT 19.050 44.085 19.450 48.585 ;
      RECT 21.500 48.585 22.000 49.085 ;
      RECT 21.950 45.085 45.700 45.585 ;
      RECT 21.550 45.085 21.950 48.585 ;
      RECT 15.950 56.735 16.450 57.235 ;
      RECT 16.400 52.235 45.700 52.735 ;
      RECT 16.000 52.235 16.400 56.735 ;
      RECT 18.750 56.735 19.250 57.235 ;
      RECT 19.200 53.235 45.700 53.735 ;
      RECT 18.800 53.235 19.200 56.735 ;
      RECT 15.950 71.785 16.450 72.285 ;
      RECT 16.400 67.285 45.700 67.785 ;
      RECT 16.000 67.285 16.400 71.785 ;
      RECT 18.750 71.785 19.250 72.285 ;
      RECT 19.200 68.285 45.700 68.785 ;
      RECT 18.800 68.285 19.200 71.785 ;
      RECT 16.400 82.335 45.700 82.835 ;
      RECT 16.000 82.335 16.400 86.885 ;
      RECT 42.000 84.335 45.700 84.835 ;
      RECT 41.600 84.335 42.000 86.885 ;
      RECT 19.400 87.285 19.800 94.485 ;
      RECT 19.200 83.335 45.700 83.835 ;
      RECT 15.800 86.885 19.800 87.285 ;
      RECT 18.800 83.335 19.200 86.885 ;
      RECT 21.000 87.285 21.400 94.485 ;
      RECT 20.200 86.885 21.400 87.285 ;
      RECT 22.600 87.285 23.000 94.485 ;
      RECT 21.800 86.885 23.000 87.285 ;
      RECT 24.200 87.285 24.600 94.485 ;
      RECT 23.400 86.885 24.600 87.285 ;
      RECT 25.800 87.285 26.200 94.485 ;
      RECT 25.000 86.885 26.200 87.285 ;
      RECT 27.400 87.285 27.800 94.485 ;
      RECT 26.600 86.885 27.800 87.285 ;
      RECT 29.000 87.285 29.400 94.485 ;
      RECT 28.200 86.885 29.400 87.285 ;
      RECT 30.600 87.285 31.000 94.485 ;
      RECT 29.800 86.885 31.000 87.285 ;
      RECT 32.200 87.285 32.600 94.485 ;
      RECT 31.400 86.885 32.600 87.285 ;
      RECT 33.800 87.285 34.200 94.485 ;
      RECT 33.000 86.885 34.200 87.285 ;
      RECT 35.400 87.285 35.800 94.485 ;
      RECT 34.600 86.885 35.800 87.285 ;
      RECT 37.000 87.285 37.400 94.485 ;
      RECT 36.200 86.885 37.400 87.285 ;
      RECT 38.600 87.285 39.000 94.485 ;
      RECT 37.800 86.885 39.000 87.285 ;
      RECT 40.200 87.285 40.600 94.485 ;
      RECT 39.400 86.885 40.600 87.285 ;
      RECT 19.400 94.485 20.600 94.885 ;
      RECT 20.200 87.285 20.600 94.485 ;
      RECT 21.000 94.485 22.200 94.885 ;
      RECT 21.800 87.285 22.200 94.485 ;
      RECT 22.600 94.485 23.800 94.885 ;
      RECT 23.400 87.285 23.800 94.485 ;
      RECT 24.200 94.485 25.400 94.885 ;
      RECT 25.000 87.285 25.400 94.485 ;
      RECT 25.800 94.485 27.000 94.885 ;
      RECT 26.600 87.285 27.000 94.485 ;
      RECT 27.400 94.485 28.600 94.885 ;
      RECT 28.200 87.285 28.600 94.485 ;
      RECT 29.000 94.485 30.200 94.885 ;
      RECT 29.800 87.285 30.200 94.485 ;
      RECT 30.600 94.485 31.800 94.885 ;
      RECT 31.400 87.285 31.800 94.485 ;
      RECT 32.200 94.485 33.400 94.885 ;
      RECT 33.000 87.285 33.400 94.485 ;
      RECT 33.800 94.485 35.000 94.885 ;
      RECT 34.600 87.285 35.000 94.485 ;
      RECT 35.400 94.485 36.600 94.885 ;
      RECT 36.200 87.285 36.600 94.485 ;
      RECT 37.000 94.485 38.200 94.885 ;
      RECT 37.800 87.285 38.200 94.485 ;
      RECT 38.600 94.485 39.800 94.885 ;
      RECT 39.400 87.285 39.800 94.485 ;
      RECT 41.000 86.885 45.000 87.285 ;
      RECT 40.200 94.485 41.400 94.885 ;
      RECT 41.000 87.285 41.400 94.485 ;
      RECT 44.800 85.335 45.700 85.835 ;
      RECT 44.400 85.335 44.800 86.885 ;
      RECT 22.835 122.670 23.815 123.000 ;
      RECT 22.835 123.320 23.815 123.650 ;
      RECT 22.835 123.970 23.815 124.300 ;
      RECT 22.835 124.620 23.815 124.950 ;
      RECT 3.100 128.670 37.500 129.170 ;
      RECT 38.500 128.670 41.050 129.170 ;
      RECT 37.500 128.420 38.500 129.420 ;
      RECT 43.250 109.535 45.700 110.035 ;
      RECT 43.250 113.085 45.700 113.585 ;
      RECT 43.250 114.585 45.700 115.085 ;
      RECT 43.250 117.835 45.700 118.335 ;
      RECT 43.250 119.335 45.700 119.835 ;
      RECT 43.250 97.635 45.700 98.135 ;
      RECT 24.135 122.670 25.115 123.000 ;
      RECT 25.435 122.670 26.415 123.000 ;
      RECT 26.735 122.670 27.715 123.000 ;
      RECT 28.035 122.670 29.015 123.000 ;
      RECT 29.335 122.670 30.315 123.000 ;
      RECT 30.635 122.670 31.615 123.000 ;
      RECT 31.935 122.670 32.915 123.000 ;
      RECT 33.235 122.670 34.215 123.000 ;
      RECT 34.535 122.670 35.515 123.000 ;
      RECT 35.835 122.670 36.815 123.000 ;
      RECT 37.135 122.670 38.115 123.000 ;
      RECT 38.435 122.670 39.415 123.000 ;
      RECT 39.735 122.670 40.715 123.000 ;
      RECT 41.035 122.670 42.015 123.000 ;
      RECT 42.335 122.670 43.250 123.000 ;
      RECT 43.250 122.585 45.700 123.085 ;
      RECT 43.250 99.435 45.700 99.935 ;
      RECT 24.135 123.320 25.115 123.650 ;
      RECT 25.435 123.320 26.415 123.650 ;
      RECT 26.735 123.320 27.715 123.650 ;
      RECT 28.035 123.320 29.015 123.650 ;
      RECT 29.335 123.320 30.315 123.650 ;
      RECT 30.635 123.320 31.615 123.650 ;
      RECT 31.935 123.320 32.915 123.650 ;
      RECT 33.235 123.320 34.215 123.650 ;
      RECT 34.535 123.320 35.515 123.650 ;
      RECT 35.835 123.320 36.815 123.650 ;
      RECT 37.135 123.320 38.115 123.650 ;
      RECT 38.435 123.320 39.415 123.650 ;
      RECT 39.735 123.320 40.715 123.650 ;
      RECT 41.035 123.320 42.015 123.650 ;
      RECT 43.250 102.685 45.700 103.185 ;
      RECT 24.135 123.970 25.115 124.300 ;
      RECT 25.435 123.970 26.415 124.300 ;
      RECT 26.735 123.970 27.715 124.300 ;
      RECT 28.035 123.970 29.015 124.300 ;
      RECT 29.335 123.970 30.315 124.300 ;
      RECT 30.635 123.970 31.615 124.300 ;
      RECT 31.935 123.970 32.915 124.300 ;
      RECT 33.235 123.970 34.215 124.300 ;
      RECT 34.535 123.970 35.515 124.300 ;
      RECT 35.835 123.970 36.815 124.300 ;
      RECT 37.135 123.970 38.115 124.300 ;
      RECT 38.435 123.970 39.415 124.300 ;
      RECT 39.735 123.970 40.715 124.300 ;
      RECT 41.035 123.970 42.015 124.300 ;
      RECT 42.335 123.320 42.665 124.300 ;
      RECT 43.250 104.485 45.700 104.985 ;
      RECT 24.135 124.620 25.115 124.950 ;
      RECT 25.435 124.620 26.415 124.950 ;
      RECT 26.735 124.620 27.715 124.950 ;
      RECT 28.035 124.620 29.015 124.950 ;
      RECT 29.335 124.620 30.315 124.950 ;
      RECT 30.635 124.620 31.615 124.950 ;
      RECT 31.935 124.620 32.915 124.950 ;
      RECT 33.235 124.620 34.215 124.950 ;
      RECT 34.535 124.620 35.515 124.950 ;
      RECT 35.835 124.620 36.815 124.950 ;
      RECT 37.135 124.620 38.115 124.950 ;
      RECT 38.435 124.620 39.415 124.950 ;
      RECT 39.735 124.620 40.715 124.950 ;
      RECT 41.035 124.620 42.015 124.950 ;
      RECT 42.335 124.620 43.250 124.950 ;
      RECT 43.250 124.535 45.700 125.035 ;
      RECT 39.245 127.535 45.700 128.035 ;
      RECT 43.250 107.735 45.700 108.235 ;
      RECT 43.300 129.725 45.700 130.225 ;
      RECT 41.060 132.935 45.700 133.435 ;
      RECT 43.250 136.185 45.700 136.685 ;
      RECT 43.250 137.985 45.700 138.485 ;
      RECT 43.250 141.235 45.700 141.735 ;
      RECT 43.250 143.035 45.700 143.535 ;
      RECT 43.250 146.285 45.700 146.785 ;
      RECT 43.250 148.085 45.700 148.585 ;
      RECT 15.035 123.320 16.015 123.650 ;
      RECT 16.335 123.320 17.315 123.650 ;
      RECT 17.635 123.320 18.615 123.650 ;
      RECT 18.935 123.320 19.915 123.650 ;
      RECT 20.235 123.320 21.215 123.650 ;
      RECT 21.535 123.320 22.515 123.650 ;
      RECT 1.100 109.535 7.000 110.035 ;
      RECT 8.000 109.535 11.850 110.035 ;
      RECT 7.000 109.285 8.000 110.285 ;
      RECT 3.100 84.335 7.000 84.835 ;
      RECT 8.000 84.335 9.250 84.835 ;
      RECT 7.000 84.085 8.000 85.085 ;
      RECT 3.100 113.085 7.000 113.585 ;
      RECT 8.000 113.085 9.250 113.585 ;
      RECT 7.000 112.835 8.000 113.835 ;
      RECT 3.100 97.635 7.000 98.135 ;
      RECT 8.000 97.635 9.250 98.135 ;
      RECT 7.000 97.385 8.000 98.385 ;
      RECT 10.485 123.970 10.815 124.950 ;
      RECT 11.135 124.620 12.115 124.950 ;
      RECT 12.435 124.620 13.415 124.950 ;
      RECT 13.735 124.620 14.715 124.950 ;
      RECT 15.035 124.620 16.015 124.950 ;
      RECT 16.335 124.620 17.315 124.950 ;
      RECT 17.635 124.620 18.615 124.950 ;
      RECT 18.935 124.620 19.915 124.950 ;
      RECT 20.235 124.620 21.215 124.950 ;
      RECT 21.535 124.620 22.515 124.950 ;
      RECT 3.100 107.735 7.000 108.235 ;
      RECT 8.000 107.735 9.250 108.235 ;
      RECT 7.000 107.485 8.000 108.485 ;
      RECT 3.100 117.835 7.000 118.335 ;
      RECT 8.000 117.835 9.250 118.335 ;
      RECT 7.000 117.585 8.000 118.585 ;
      RECT 3.100 102.685 7.000 103.185 ;
      RECT 8.000 102.685 9.250 103.185 ;
      RECT 7.000 102.435 8.000 103.435 ;
      RECT 11.135 122.670 12.115 123.000 ;
      RECT 12.435 122.670 13.415 123.000 ;
      RECT 13.735 122.670 14.715 123.000 ;
      RECT 15.035 122.670 16.015 123.000 ;
      RECT 16.335 122.670 17.315 123.000 ;
      RECT 17.635 122.670 18.615 123.000 ;
      RECT 18.935 122.670 19.915 123.000 ;
      RECT 20.235 122.670 21.215 123.000 ;
      RECT 11.135 123.970 12.115 124.300 ;
      RECT 12.435 123.970 13.415 124.300 ;
      RECT 13.735 123.970 14.715 124.300 ;
      RECT 15.035 123.970 16.015 124.300 ;
      RECT 16.335 123.970 17.315 124.300 ;
      RECT 17.635 123.970 18.615 124.300 ;
      RECT 18.935 123.970 19.915 124.300 ;
      RECT 20.235 123.970 21.215 124.300 ;
      RECT 21.535 123.970 22.515 124.300 ;
      RECT 21.535 122.670 22.515 123.000 ;
      RECT 3.100 136.185 7.000 136.685 ;
      RECT 8.000 136.185 9.250 136.685 ;
      RECT 7.000 135.935 8.000 136.935 ;
      RECT 3.100 122.585 7.000 123.085 ;
      RECT 8.000 122.585 9.250 123.085 ;
      RECT 7.000 122.335 8.000 123.335 ;
      RECT 10.485 122.670 10.815 123.650 ;
      RECT 3.100 141.235 7.000 141.735 ;
      RECT 8.000 141.235 9.250 141.735 ;
      RECT 7.000 140.985 8.000 141.985 ;
      RECT 11.135 123.320 12.115 123.650 ;
      RECT 12.435 123.320 13.415 123.650 ;
      RECT 3.100 146.285 7.000 146.785 ;
      RECT 8.000 146.285 9.250 146.785 ;
      RECT 7.000 146.035 8.000 147.035 ;
      RECT 13.735 123.320 14.715 123.650 ;
      RECT 1.100 148.085 7.000 148.585 ;
      RECT 8.000 148.085 11.850 148.585 ;
      RECT 7.000 147.835 8.000 148.835 ;
      RECT 3.100 46.085 7.000 46.585 ;
      RECT 8.000 46.085 9.250 46.585 ;
      RECT 7.000 45.835 8.000 46.835 ;
      RECT 3.100 22.155 7.000 22.655 ;
      RECT 8.000 22.155 9.250 22.655 ;
      RECT 7.000 21.905 8.000 22.905 ;
      RECT 3.100 6.100 7.000 6.600 ;
      RECT 8.000 6.100 9.250 6.600 ;
      RECT 7.000 5.850 8.000 6.850 ;
      RECT 1.100 48.585 7.000 49.085 ;
      RECT 8.000 48.585 17.950 49.085 ;
      RECT 7.000 48.335 8.000 49.335 ;
      RECT 3.100 54.235 7.000 54.735 ;
      RECT 8.000 54.235 9.250 54.735 ;
      RECT 7.000 53.985 8.000 54.985 ;
      RECT 3.100 38.210 7.000 38.710 ;
      RECT 8.000 38.210 9.250 38.710 ;
      RECT 7.000 37.960 8.000 38.960 ;
      RECT 3.100 14.000 7.000 14.500 ;
      RECT 8.000 14.000 9.250 14.500 ;
      RECT 7.000 13.750 8.000 14.750 ;
      RECT 3.100 69.285 7.000 69.785 ;
      RECT 8.000 69.285 9.250 69.785 ;
      RECT 7.000 69.035 8.000 70.035 ;
      RECT 3.100 30.055 7.000 30.555 ;
      RECT 8.000 30.055 9.250 30.555 ;
      RECT 7.000 29.805 8.000 30.805 ;
      RECT 43.670 32.555 44.170 33.055 ;
      RECT 44.120 31.055 45.700 31.555 ;
      RECT 43.720 31.055 44.120 32.555 ;
      RECT 39.510 16.500 40.010 17.000 ;
      RECT 39.960 14.000 45.700 14.500 ;
      RECT 39.560 14.000 39.960 16.500 ;
      RECT 39.510 24.655 40.010 25.155 ;
      RECT 39.960 22.155 45.700 22.655 ;
      RECT 39.560 22.155 39.960 24.655 ;
      RECT 41.550 56.735 42.050 57.235 ;
      RECT 42.000 54.235 45.700 54.735 ;
      RECT 41.600 54.235 42.000 56.735 ;
      RECT 44.800 55.235 45.700 55.735 ;
      RECT 44.400 55.235 44.800 56.735 ;
      RECT 44.350 56.735 44.850 57.235 ;
      RECT 43.670 24.655 44.170 25.155 ;
      RECT 44.120 23.155 45.700 23.655 ;
      RECT 43.720 23.155 44.120 24.655 ;
      RECT 42.000 40.710 42.500 41.210 ;
      RECT 42.450 38.210 45.700 38.710 ;
      RECT 42.050 38.210 42.450 40.710 ;
      RECT 44.550 39.210 45.700 39.710 ;
      RECT 44.550 39.710 44.950 40.710 ;
      RECT 44.500 40.710 45.000 41.210 ;
      RECT 41.550 71.785 42.050 72.285 ;
      RECT 42.000 69.285 45.700 69.785 ;
      RECT 41.600 69.285 42.000 71.785 ;
      RECT 44.800 70.285 45.700 70.785 ;
      RECT 44.400 70.285 44.800 71.785 ;
      RECT 44.350 71.785 44.850 72.285 ;
      RECT 43.670 16.500 44.170 17.000 ;
      RECT 44.120 15.000 45.700 15.500 ;
      RECT 43.720 15.000 44.120 16.500 ;
      RECT 43.670 8.600 44.170 9.100 ;
      RECT 44.120 7.100 45.700 7.600 ;
      RECT 43.720 7.100 44.120 8.600 ;
      RECT 39.510 8.600 40.010 9.100 ;
      RECT 39.960 6.100 45.700 6.600 ;
      RECT 39.560 6.100 39.960 8.600 ;
      RECT 42.000 48.585 42.500 49.085 ;
      RECT 42.450 46.085 45.700 46.585 ;
      RECT 42.050 46.085 42.450 48.585 ;
      RECT 44.550 47.085 45.700 47.585 ;
      RECT 44.550 47.585 44.950 48.585 ;
      RECT 44.500 48.585 45.000 49.085 ;
      RECT 39.510 32.555 40.010 33.055 ;
      RECT 39.960 30.055 45.700 30.555 ;
      RECT 39.560 30.055 39.960 32.555 ;
  END
END tp_bandr

END LIBRARY
